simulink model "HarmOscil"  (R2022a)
settings: Solver=VariableStepAuto  StartTime=0.0  StopTime=20  RelTol=1e-3
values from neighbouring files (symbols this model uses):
  k = 9e9    (= 9000000000)    [electDipole.m]    (also in solvGasSei.m = 1; solvJacobi.m = 1; solvSOR.m = 1; solvSORerr.m = 1)
  m = 4*m    (= 4)    [rom_int.m]    (also in FreeOscil_Displace_Test01.m = 1; vspring.m = 1)
undefined symbols (not defined in the file or in its folder): f, wf

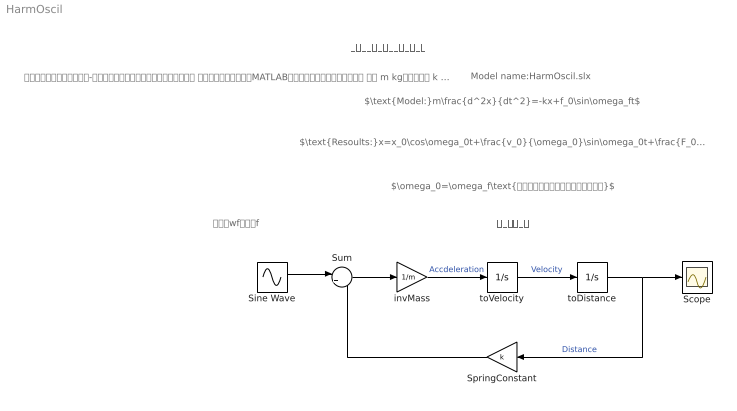
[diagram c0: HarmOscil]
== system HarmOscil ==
  note: 初期値はゼロ
  note: $\omega_0=\omega_f\text{この条件の時に系は共振状態になる}$
  note: 周波数wf，振幅f
  note: $\text{Resoults:}x=x_0\cos\omega_0t+\frac{v_0}{\omega_0}\sin\omega_0t+\frac{F_0}{\omega_0^2-\omega_f^2}\sin\omega_ft$
  note: $\text{Model:}m\frac{d^2x}{dt^2}=-kx+f_0\sin\omega_ft$
  note: 外力による自由振動（マス‐ばね系）のシミュレーションモデルです． モデルのパラメータはMATLABワークスペースで設定します． 質量 m kg，ばね係数 k 外力wf rad/s，振幅 f
  note: Model name:HarmOscil.slx
  note: 強制力による調和振動系モデル
  Scope : Scope
  Sine Wave : Sin  Amplitude=f  Frequency=wf  SampleTime=0
  SpringConstant : Gain  Gain=k
  Sum : Sum  Inputs=|+-
  invMass : Gain  Gain=1/m
  toDistance : Integrator
  toVelocity : Integrator
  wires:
  invMass/1 -> toVelocity/1  "Accdeleration"
  toVelocity/1 -> toDistance/1  "Velocity"
  Sum/1 -> invMass/1
  Sine Wave/1 -> Sum/1
  SpringConstant/1 -> Sum/2
  toDistance/1 -> SpringConstant/1, Scope/1  "Distance"
